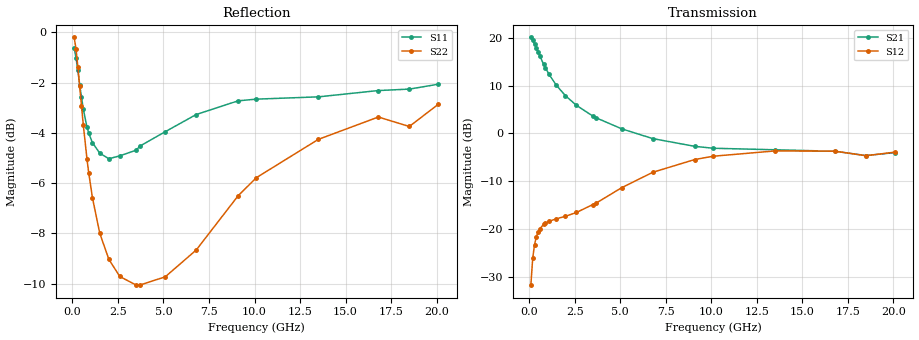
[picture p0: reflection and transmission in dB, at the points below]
!  Infineon Technologies AG
! BFR380L3 , PF131585-7, No.6, Th 09.10.01, soldered on pcb-board, measured with PP GSG850
!  Vce=6.0 V,  Ic=3.0 mA
! Common Emitter S-Parameters:  15. November 2001
#  GHz  S  MA  R  50
! f  S11  S21  S12  S22
! GHz  Mag  Ang  Mag  Ang  Mag  Ang  Mag  Ang
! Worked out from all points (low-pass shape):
!   201 points, 100 MHz to 20.1 GHz, reference 50 ohm
!   highest |S21| = 20.08 dB at 100 MHz (marker M1); lowest = -4.6 dB at 18.5 GHz (marker M2)
!   |S21| within 3 dB of the highest: start of sweep to 491.6 MHz
!   lowest |S11| = -5.0 dB at 2 GHz (marker M3), VSWR 3.55, Z = 14.2 - j3.66 ohm
!   |S11| at or under -10 dB: nowhere
!   |S22| runs from -10.1 to -0.2 dB; largest |S21 - S12| = 10
!   S11 on the Smith chart (normalised r, x): 100 MHz: 1.21, -5.56; 500 MHz: 0.33, -1.08; 1.1 GHz: 0.29, -0.40; 3.7 GHz: 0.27, +0.25; 9.1 GHz: 0.33, +1.04; 20.1 GHz: 0.96, +2.51
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0.1  0.93 -19.5  10.09 166.4  0.02583 76.9  0.9768 -10.4
0.2  0.889 -38.0  9.405 154.1  0.04947 69.6  0.9255 -20.0
0.3  0.84 -54.8  8.663 143.0  0.06841 61.1  0.8542 -28.0
0.4  0.7866 -69.8  7.859 133.6  0.08255 54.3  0.7812 -34.4
0.5  0.7432 -82.7  7.083 125.6  0.09315 49.2  0.7139 -39.5
0.6  0.703 -94.0  6.395 118.9  0.1009 45.2  0.6539 -43.5
0.8  0.6481 -112.5  5.283 107.9  0.1113 40.0  0.5602 -49.2
0.9  0.6295 -120.2  4.84 103.6  0.1149 38.2  0.5243 -51.2
1.1  0.6032 -133.2  4.132 95.9  0.1204 36.0  0.469 -54.5
1.5  0.575 -153.1  3.182 83.9  0.1275 35.1  0.3987 -59.4
2  0.5604 -170.9  2.474 72.1  0.1357 37.1  0.3537 -65.2
2.6  0.5677 172.8  1.964 60.4  0.1486 41.5  0.3268 -73.2
3.5  0.5827 153.7  1.517 45.8  0.1798 47.9  0.3142 -87.2
3.7  0.5935 150.5  1.449 43.2  0.1871 48.7  0.3141 -91.4
5.1  0.6342 127.9  1.113 25.7  0.2711 50.6  0.3263 -118.5
6.8  0.6861 106.3  0.8803 10.9  0.3917 43.1  0.3689 -155.2
9.1  0.7305 84.8  0.7313 -0.9  0.5323 25.9  0.4729 163.2
10.1  0.7362 77.1  0.6985 -4.6  0.5759 18.1  0.5137 147.7
13.5  0.7439 58.9  0.6732 -17.9  0.6546 -6.5  0.6122 108.0
16.8  0.7657 47.2  0.6494 -29.8  0.6502 -24.1  0.6783 82.0
18.5  0.7708 45.5  0.5855 -37.5  0.5836 -32.7  0.6495 75.3
20.1  0.7883 38.8  0.6295 -41.5  0.6361 -38.1  0.7194 64.0
